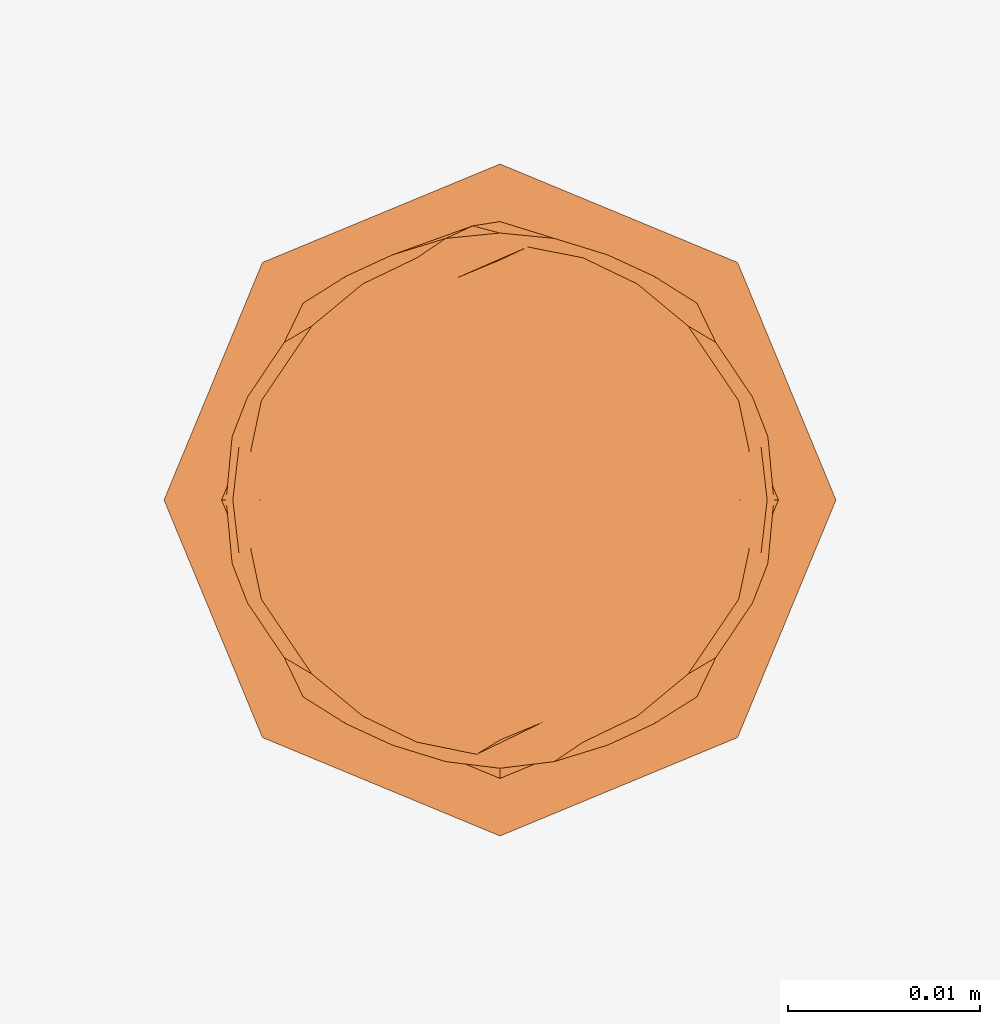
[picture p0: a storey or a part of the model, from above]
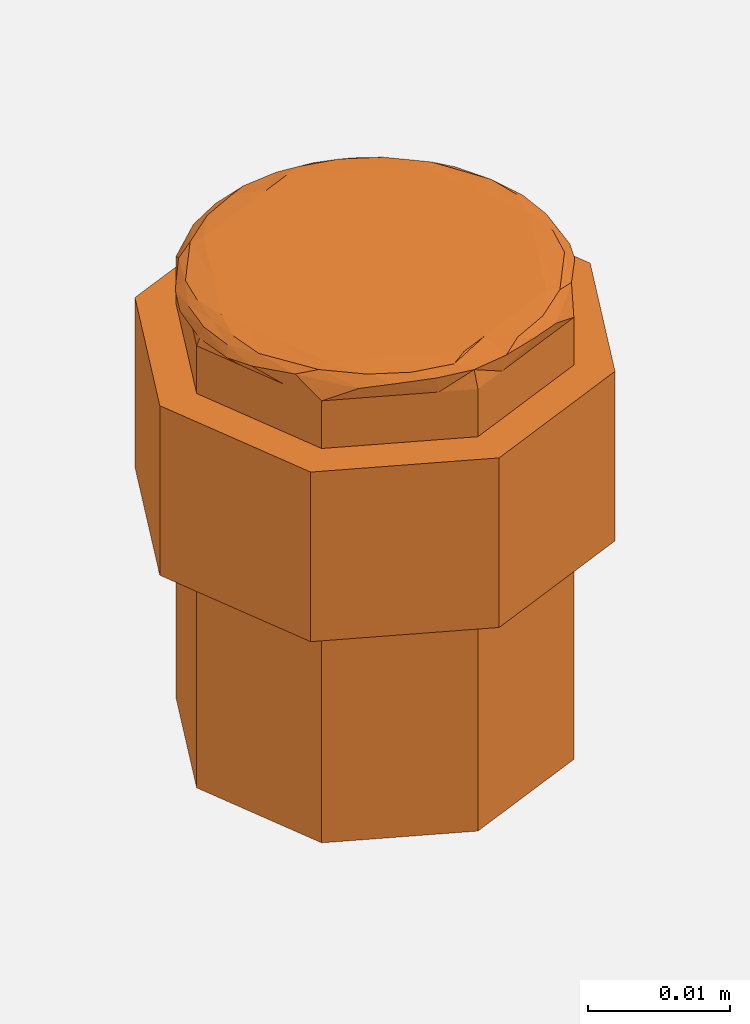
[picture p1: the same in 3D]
Properties of the parts of a building model (IFC2X3)

# File
Description: ViewDefinition [COBie2.4DesignDeliverable]
File name: Project Number
Time: 2023-04-07T11:36:39
Written by: The EXPRESS Data Manager Version 5.02.0100.07 : 28 Aug 2013
Made in: 20211019_1515(x64) - Exporter 20.2.60.15 - Alternate UI 20.2.60.15
Comment: STEP Physical File produced by: The EXPRESS Data Manager Version 5.02.0100.07 : 28 Aug 2013 * Module: EDMstepFileFactory/EDMstandAlone * Creation date: Fri Apr 07 11:36:39 2023 * Host: DESKTOP-KN3O7NT * Database: C:\Users\SARAHS~1\AppData\Local\Temp\c7e508df-9a2f-4df8-9830-52c09c4cd7c5\880bd076-0084-43a3-9b0f-cef307924c8a\ifc * Database version: 5507 * Database creation date: Fri Apr 07 11:36:38 2023 * Schema: IFC2X3 * Model: DataRepository.ifc * Model creation date: Fri Apr 07 11:36:38 2023 * Header model: DataRepository.ifc_HeaderModel * Header model creation date: Fri Apr 07 11:36:38 2023 * EDMuser: sdai-user * EDMgroup: sdai-group * License ID and type: 5605 : Permanent license. Expiry date: * EDMstepFileFactory options: 020000

# IfcProject, Project Number
LongName: Project Name; Phase: Awaiting Approval

# IfcSite, Default
RefLatitude: 51, 30, 23, 112487; RefLongitude: 0, -7, -37, -956022; RefElevation: 0 mm

# IfcBuilding, n/a
LongName: n/a
Pset_BuildingCommon - NumberOfStoreys: 1
Pset_ProductRequirements - Category: Project Information

# IfcBuildingStorey: Level:Circle Head - Project Datum, Level 0
In: n/a
LongName: Level 0; Elevation: 0 mm
Pset_AirSideSystemInformation - Name: Level 0
Pset_ProductRequirements - Name: Level 0; Category: Levels

# IfcBuildingElementProxy: DBLTD_Duten_DoorStops_Q965:Brushed Brass Door Stop, (7)
In: Level 0
Type - Material: DBLTD_Duten_Metal_BrushedBrass
Type - Pset_BuildingElementProxyCommon - Reference: Brushed Brass Door Stop
Type - Pset_ElementShading - Color: Variable
Type - Pset_ManufacturerTypeInformation - ModelReference: Brushed Brass Door Stop; Manufacturer: Duten
Type - Pset_ProductRequirements - Name: Pull Handle; Category: Generic Models
Type - Pset_QuantityTakeOff - Reference: Brushed Brass Door Stop
Pset_BuildingElementProxyCommon - sets with these values: 2

# IfcBuildingElementProxy: DBLTD_Duten_DoorStops_Q965:Brushed Copper Door Stop, (9)
In: Level 0
Type - Material: DBLTD_Duten_Metal_BrushedCopper
Type - Pset_BuildingElementProxyCommon - Reference: Brushed Copper Door Stop
Type - Pset_ElementShading - Color: Variable
Type - Pset_ManufacturerTypeInformation - ModelReference: Brushed Copper Door Stop; Manufacturer: Duten
Type - Pset_ProductRequirements - Name: Pull Handle; Category: Generic Models
Type - Pset_QuantityTakeOff - Reference: Brushed Copper Door Stop
Pset_BuildingElementProxyCommon - sets with these values: 2

# IfcBuildingElementProxy: DBLTD_Duten_DoorStops_Q965:Brushed Stainless Steel Door Stop, (11)
In: Level 0
Type - Material: DBLTD_Duten_Metal_BrushedStainlessSteel
Type - Pset_BuildingElementProxyCommon - Reference: Brushed Stainless Steel Door Stop
Type - Pset_ElementShading - Color: Variable
Type - Pset_ManufacturerTypeInformation - ModelReference: Brushed Stainless Door Stop; Manufacturer: Duten
Type - Pset_ProductRequirements - Name: Pull Handle; Category: Generic Models
Type - Pset_QuantityTakeOff - Reference: Brushed Stainless Steel Door Stop
Pset_BuildingElementProxyCommon - sets with these values: 2

# IfcBuildingElementProxy: DBLTD_Duten_DoorStops_Q965:Chrome Door Stop, (13)
In: Level 0
Type - Material: DBLTD_Duten_Metal_Chrome
Type - Pset_BuildingElementProxyCommon - Reference: Chrome Door Stop
Type - Pset_ElementShading - Color: Variable
Type - Pset_ManufacturerTypeInformation - ModelReference: Chrome Door Stop; Manufacturer: Duten
Type - Pset_ProductRequirements - Name: Pull Handle; Category: Generic Models
Type - Pset_QuantityTakeOff - Reference: Chrome Door Stop
Pset_BuildingElementProxyCommon - sets with these values: 2

# IfcBuildingElementProxy: DBLTD_Duten_DoorStops_Q965:Matte Black Door Stop, (15)
In: Level 0
Type - Material: DBLTD_Duten_Metal_MatteBlack
Type - Pset_BuildingElementProxyCommon - Reference: Matte Black Door Stop
Type - Pset_ElementShading - Color: Variable
Type - Pset_ManufacturerTypeInformation - ModelReference: Matte Black Door Stop; Manufacturer: Duten
Type - Pset_ProductRequirements - Name: Pull Handle; Category: Generic Models
Type - Pset_QuantityTakeOff - Reference: Matte Black Door Stop
Pset_BuildingElementProxyCommon - sets with these values: 2

# IfcSlab: Floor:Floor-Grnd-Susp_65Scr-80Ins-100Blk-75PC, (4)
In: Level 0
Type - PredefinedType: FLOOR; Material: Concrete, Sand/Cement Screed 65 mm, Rigid insulation 80 mm, Air 150 mm, Concrete Masonry, Floor Block 100 mm, Concrete, Precast 75 mm
Type - Pset_ElementShading - Roughness: 914.4 mm
Type - Pset_ProductRequirements - Category: Floors
Type - Pset_QuantityTakeOff - Reference: Floor-Grnd-Susp_65Scr-80Ins-100Blk-75PC
Type - Pset_ReinforcementBarPitchOfSlab - Reference: Floor-Grnd-Susp_65Scr-80Ins-100Blk-75PC
Type - Pset_SlabCommon - Reference: Floor-Grnd-Susp_65Scr-80Ins-100Blk-75PC; IsExternal: no; ThermalTransmittance: 0.117438 kg/K/s3
Pset_QuantityTakeOff - sets with these values: 2
Pset_SlabCommon - LoadBearing: no; PitchAngle: 0 deg
BaseQuantities - GrossArea: 4 m2; NetArea: 11.76 m2; GrossVolume: 1880 m3; NetVolume: 1.88 m3; Perimeter: 8000 mm; Width: 470 mm
